VERSION 5.8 ;
BUSBITCHARS "[]" ;
DIVIDERCHAR "/" ;
CLEARANCEMEASURE EUCLIDEAN ;

SITE coresite
    SIZE 0.0450 BY 0.1680 ;
    CLASS CORE ;
    SYMMETRY Y ;
END coresite

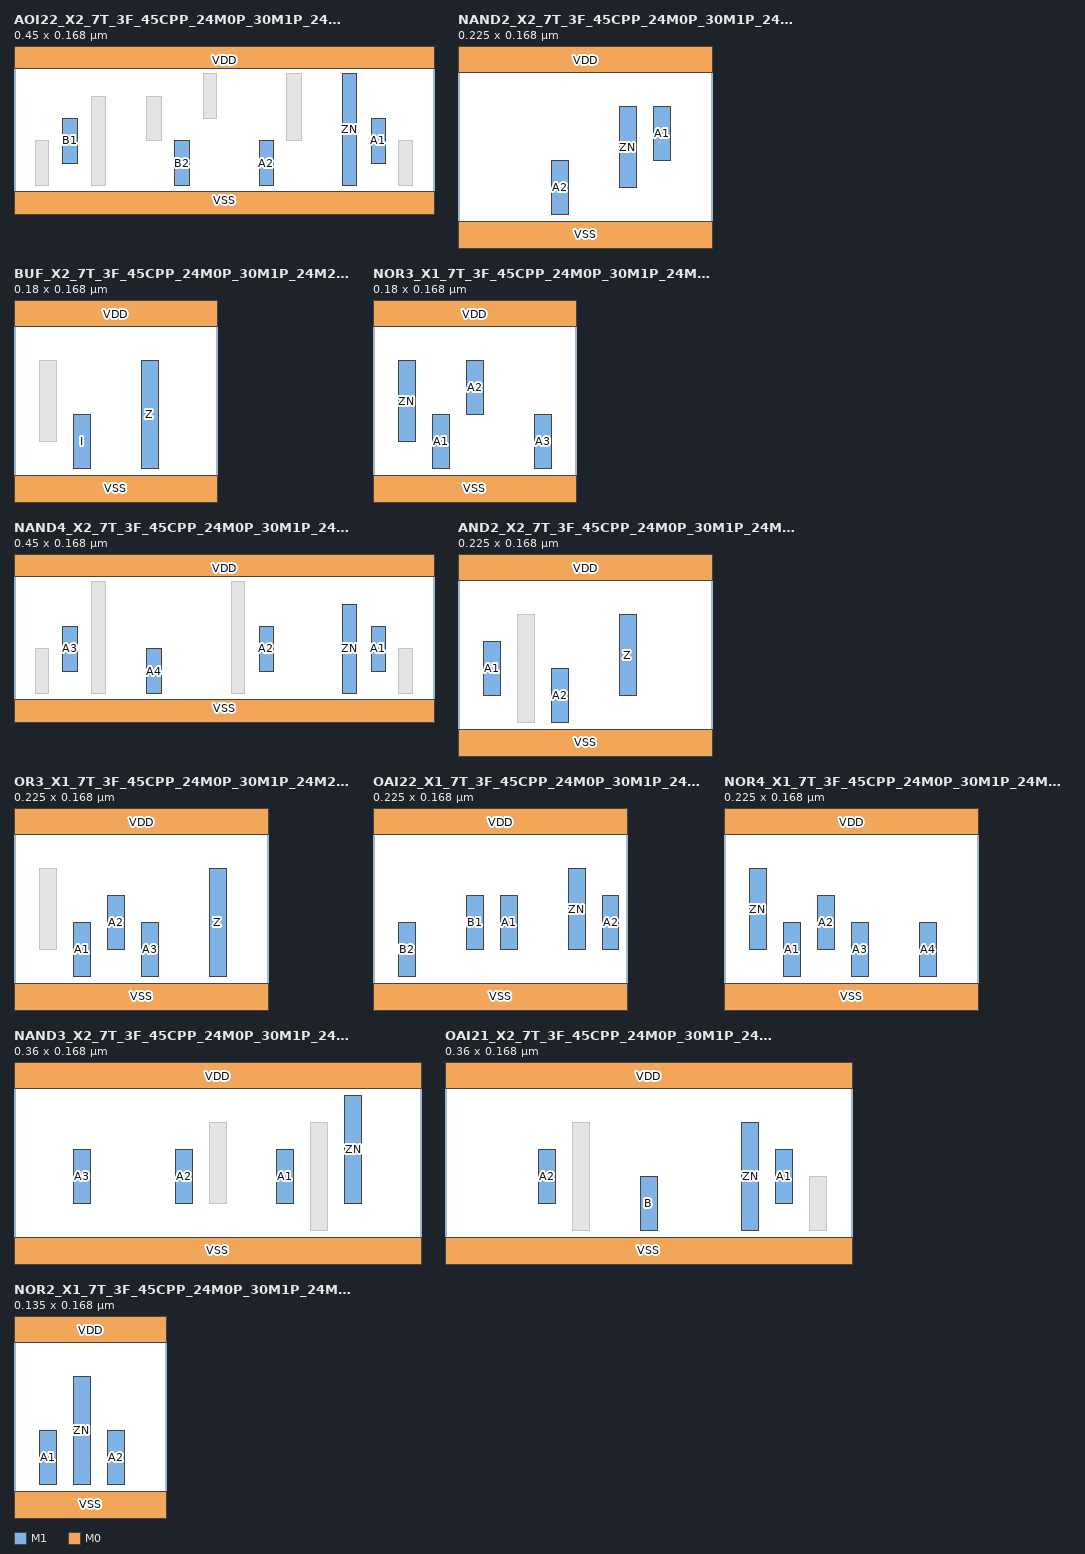
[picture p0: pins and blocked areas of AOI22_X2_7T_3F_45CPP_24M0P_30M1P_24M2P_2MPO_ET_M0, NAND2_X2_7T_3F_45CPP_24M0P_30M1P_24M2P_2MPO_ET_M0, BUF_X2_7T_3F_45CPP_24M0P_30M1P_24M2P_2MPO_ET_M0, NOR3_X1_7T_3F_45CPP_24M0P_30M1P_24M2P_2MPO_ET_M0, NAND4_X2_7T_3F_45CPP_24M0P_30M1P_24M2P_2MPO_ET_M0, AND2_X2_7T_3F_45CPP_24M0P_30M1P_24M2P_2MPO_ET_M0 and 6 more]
MACRO AOI22_X2_7T_3F_45CPP_24M0P_30M1P_24M2P_2MPO_ET_M0
  CLASS CORE ;
  ORIGIN 0 0 ;
  FOREIGN AOI22_X2_7T_3F_45CPP_24M0P_30M1P_24M2P_2MPO_ET_M0 0 0 ;
  SIZE 0.4500 BY 0.1680 ;
  SYMMETRY X Y ;
  SITE coresite ;
  PIN A1
    DIRECTION INPUT ;
    USE SIGNAL ;
    PORT
      LAYER M1 ;
        RECT 0.3825 0.0960 0.3975 0.0480 ;
    END
  END A1
  PIN A2
    DIRECTION INPUT ;
    USE SIGNAL ;
    PORT
      LAYER M1 ;
        RECT 0.2625 0.0720 0.2775 0.0240 ;
    END
  END A2
  PIN ZN
    DIRECTION OUTPUT ;
    USE SIGNAL ;
    PORT
      LAYER M1 ;
        RECT 0.3525 0.1440 0.3675 0.0240 ;
    END
  END ZN
  PIN B1
    DIRECTION INPUT ;
    USE SIGNAL ;
    PORT
      LAYER M1 ;
        RECT 0.0525 0.0960 0.0675 0.0480 ;
    END
  END B1
  PIN B2
    DIRECTION INPUT ;
    USE SIGNAL ;
    PORT
      LAYER M1 ;
        RECT 0.1725 0.0720 0.1875 0.0240 ;
    END
  END B2
  PIN VDD
    DIRECTION INOUT ;
    USE POWER ;
    SHAPE ABUTMENT ;
    PORT
      LAYER M0 ;
        RECT 0.0000 0.1500 0.4500 0.1860 ;
    END
  END VDD
  PIN VSS
    DIRECTION INOUT ;
    USE GROUND ;
    SHAPE ABUTMENT ;
    PORT
      LAYER M0 ;
        RECT 0.0000 -0.0180 0.4500 0.0180 ;
    END
  END VSS
  OBS
      LAYER M1 ;
        RECT 0.0225 0.0720 0.0375 0.0240 ;
        RECT 0.2025 0.1440 0.2175 0.0960 ;
        RECT 0.4125 0.0720 0.4275 0.0240 ;
        RECT 0.1425 0.1200 0.1575 0.0720 ;
        RECT 0.0825 0.1200 0.0975 0.0240 ;
        RECT 0.2925 0.1440 0.3075 0.0720 ;
  END
END AOI22_X2_7T_3F_45CPP_24M0P_30M1P_24M2P_2MPO_ET_M0

MACRO NAND2_X2_7T_3F_45CPP_24M0P_30M1P_24M2P_2MPO_ET_M0
  CLASS CORE ;
  ORIGIN 0 0 ;
  FOREIGN NAND2_X2_7T_3F_45CPP_24M0P_30M1P_24M2P_2MPO_ET_M0 0 0 ;
  SIZE 0.2250 BY 0.1680 ;
  SYMMETRY X Y ;
  SITE coresite ;
  PIN A2
    DIRECTION INPUT ;
    USE SIGNAL ;
    PORT
      LAYER M1 ;
        RECT 0.0825 0.0720 0.0975 0.0240 ;
    END
  END A2
  PIN A1
    DIRECTION INPUT ;
    USE SIGNAL ;
    PORT
      LAYER M1 ;
        RECT 0.1725 0.1200 0.1875 0.0720 ;
    END
  END A1
  PIN ZN
    DIRECTION OUTPUT ;
    USE SIGNAL ;
    PORT
      LAYER M1 ;
        RECT 0.1425 0.1200 0.1575 0.0480 ;
    END
  END ZN
  PIN VDD
    DIRECTION INOUT ;
    USE POWER ;
    SHAPE ABUTMENT ;
    PORT
      LAYER M0 ;
        RECT 0.0000 0.1500 0.2250 0.1860 ;
    END
  END VDD
  PIN VSS
    DIRECTION INOUT ;
    USE GROUND ;
    SHAPE ABUTMENT ;
    PORT
      LAYER M0 ;
        RECT 0.0000 -0.0180 0.2250 0.0180 ;
    END
  END VSS
END NAND2_X2_7T_3F_45CPP_24M0P_30M1P_24M2P_2MPO_ET_M0

MACRO BUF_X2_7T_3F_45CPP_24M0P_30M1P_24M2P_2MPO_ET_M0
  CLASS CORE ;
  ORIGIN 0 0 ;
  FOREIGN BUF_X2_7T_3F_45CPP_24M0P_30M1P_24M2P_2MPO_ET_M0 0 0 ;
  SIZE 0.1800 BY 0.1680 ;
  SYMMETRY X Y ;
  SITE coresite ;
  PIN Z
    DIRECTION OUTPUT ;
    USE SIGNAL ;
    PORT
      LAYER M1 ;
        RECT 0.1125 0.1200 0.1275 0.0240 ;
    END
  END Z
  PIN I
    DIRECTION INPUT ;
    USE SIGNAL ;
    PORT
      LAYER M1 ;
        RECT 0.0525 0.0720 0.0675 0.0240 ;
    END
  END I
  PIN VDD
    DIRECTION INOUT ;
    USE POWER ;
    SHAPE ABUTMENT ;
    PORT
      LAYER M0 ;
        RECT 0.0000 0.1500 0.1800 0.1860 ;
    END
  END VDD
  PIN VSS
    DIRECTION INOUT ;
    USE GROUND ;
    SHAPE ABUTMENT ;
    PORT
      LAYER M0 ;
        RECT 0.0000 -0.0180 0.1800 0.0180 ;
    END
  END VSS
  OBS
      LAYER M1 ;
        RECT 0.0225 0.1200 0.0375 0.0480 ;
  END
END BUF_X2_7T_3F_45CPP_24M0P_30M1P_24M2P_2MPO_ET_M0

MACRO NOR3_X1_7T_3F_45CPP_24M0P_30M1P_24M2P_2MPO_ET_M0
  CLASS CORE ;
  ORIGIN 0 0 ;
  FOREIGN NOR3_X1_7T_3F_45CPP_24M0P_30M1P_24M2P_2MPO_ET_M0 0 0 ;
  SIZE 0.1800 BY 0.1680 ;
  SYMMETRY X Y ;
  SITE coresite ;
  PIN A3
    DIRECTION INPUT ;
    USE SIGNAL ;
    PORT
      LAYER M1 ;
        RECT 0.1425 0.0720 0.1575 0.0240 ;
    END
  END A3
  PIN A2
    DIRECTION INPUT ;
    USE SIGNAL ;
    PORT
      LAYER M1 ;
        RECT 0.0825 0.1200 0.0975 0.0720 ;
    END
  END A2
  PIN A1
    DIRECTION INPUT ;
    USE SIGNAL ;
    PORT
      LAYER M1 ;
        RECT 0.0525 0.0720 0.0675 0.0240 ;
    END
  END A1
  PIN ZN
    DIRECTION OUTPUT ;
    USE SIGNAL ;
    PORT
      LAYER M1 ;
        RECT 0.0225 0.1200 0.0375 0.0480 ;
    END
  END ZN
  PIN VDD
    DIRECTION INOUT ;
    USE POWER ;
    SHAPE ABUTMENT ;
    PORT
      LAYER M0 ;
        RECT 0.0000 0.1500 0.1800 0.1860 ;
    END
  END VDD
  PIN VSS
    DIRECTION INOUT ;
    USE GROUND ;
    SHAPE ABUTMENT ;
    PORT
      LAYER M0 ;
        RECT 0.0000 -0.0180 0.1800 0.0180 ;
    END
  END VSS
END NOR3_X1_7T_3F_45CPP_24M0P_30M1P_24M2P_2MPO_ET_M0

MACRO NAND4_X2_7T_3F_45CPP_24M0P_30M1P_24M2P_2MPO_ET_M0
  CLASS CORE ;
  ORIGIN 0 0 ;
  FOREIGN NAND4_X2_7T_3F_45CPP_24M0P_30M1P_24M2P_2MPO_ET_M0 0 0 ;
  SIZE 0.4500 BY 0.1680 ;
  SYMMETRY X Y ;
  SITE coresite ;
  PIN ZN
    DIRECTION OUTPUT ;
    USE SIGNAL ;
    PORT
      LAYER M1 ;
        RECT 0.3525 0.1200 0.3675 0.0240 ;
    END
  END ZN
  PIN A1
    DIRECTION INPUT ;
    USE SIGNAL ;
    PORT
      LAYER M1 ;
        RECT 0.3825 0.0960 0.3975 0.0480 ;
    END
  END A1
  PIN A2
    DIRECTION INPUT ;
    USE SIGNAL ;
    PORT
      LAYER M1 ;
        RECT 0.2625 0.0960 0.2775 0.0480 ;
    END
  END A2
  PIN A3
    DIRECTION INPUT ;
    USE SIGNAL ;
    PORT
      LAYER M1 ;
        RECT 0.0525 0.0960 0.0675 0.0480 ;
    END
  END A3
  PIN A4
    DIRECTION INPUT ;
    USE SIGNAL ;
    PORT
      LAYER M1 ;
        RECT 0.1425 0.0720 0.1575 0.0240 ;
    END
  END A4
  PIN VDD
    DIRECTION INOUT ;
    USE POWER ;
    SHAPE ABUTMENT ;
    PORT
      LAYER M0 ;
        RECT 0.0000 0.1500 0.4500 0.1860 ;
    END
  END VDD
  PIN VSS
    DIRECTION INOUT ;
    USE GROUND ;
    SHAPE ABUTMENT ;
    PORT
      LAYER M0 ;
        RECT 0.0000 -0.0180 0.4500 0.0180 ;
    END
  END VSS
  OBS
      LAYER M1 ;
        RECT 0.0825 0.1440 0.0975 0.0240 ;
        RECT 0.2325 0.1440 0.2475 0.0240 ;
        RECT 0.0225 0.0720 0.0375 0.0240 ;
        RECT 0.4125 0.0720 0.4275 0.0240 ;
  END
END NAND4_X2_7T_3F_45CPP_24M0P_30M1P_24M2P_2MPO_ET_M0

MACRO AND2_X2_7T_3F_45CPP_24M0P_30M1P_24M2P_2MPO_ET_M0
  CLASS CORE ;
  ORIGIN 0 0 ;
  FOREIGN AND2_X2_7T_3F_45CPP_24M0P_30M1P_24M2P_2MPO_ET_M0 0 0 ;
  SIZE 0.2250 BY 0.1680 ;
  SYMMETRY X Y ;
  SITE coresite ;
  PIN Z
    DIRECTION OUTPUT ;
    USE SIGNAL ;
    PORT
      LAYER M1 ;
        RECT 0.1425 0.1200 0.1575 0.0480 ;
    END
  END Z
  PIN A1
    DIRECTION INPUT ;
    USE SIGNAL ;
    PORT
      LAYER M1 ;
        RECT 0.0225 0.0960 0.0375 0.0480 ;
    END
  END A1
  PIN A2
    DIRECTION INPUT ;
    USE SIGNAL ;
    PORT
      LAYER M1 ;
        RECT 0.0825 0.0720 0.0975 0.0240 ;
    END
  END A2
  PIN VDD
    DIRECTION INOUT ;
    USE POWER ;
    SHAPE ABUTMENT ;
    PORT
      LAYER M0 ;
        RECT 0.0000 0.1500 0.2250 0.1860 ;
    END
  END VDD
  PIN VSS
    DIRECTION INOUT ;
    USE GROUND ;
    SHAPE ABUTMENT ;
    PORT
      LAYER M0 ;
        RECT 0.0000 -0.0180 0.2250 0.0180 ;
    END
  END VSS
  OBS
      LAYER M1 ;
        RECT 0.0525 0.1200 0.0675 0.0240 ;
  END
END AND2_X2_7T_3F_45CPP_24M0P_30M1P_24M2P_2MPO_ET_M0

MACRO OR3_X1_7T_3F_45CPP_24M0P_30M1P_24M2P_2MPO_ET_M0
  CLASS CORE ;
  ORIGIN 0 0 ;
  FOREIGN OR3_X1_7T_3F_45CPP_24M0P_30M1P_24M2P_2MPO_ET_M0 0 0 ;
  SIZE 0.2250 BY 0.1680 ;
  SYMMETRY X Y ;
  SITE coresite ;
  PIN Z
    DIRECTION OUTPUT ;
    USE SIGNAL ;
    PORT
      LAYER M1 ;
        RECT 0.1725 0.1200 0.1875 0.0240 ;
    END
  END Z
  PIN A1
    DIRECTION INPUT ;
    USE SIGNAL ;
    PORT
      LAYER M1 ;
        RECT 0.0525 0.0720 0.0675 0.0240 ;
    END
  END A1
  PIN A2
    DIRECTION INPUT ;
    USE SIGNAL ;
    PORT
      LAYER M1 ;
        RECT 0.0825 0.0960 0.0975 0.0480 ;
    END
  END A2
  PIN A3
    DIRECTION INPUT ;
    USE SIGNAL ;
    PORT
      LAYER M1 ;
        RECT 0.1125 0.0720 0.1275 0.0240 ;
    END
  END A3
  PIN VDD
    DIRECTION INOUT ;
    USE POWER ;
    SHAPE ABUTMENT ;
    PORT
      LAYER M0 ;
        RECT 0.0000 0.1500 0.2250 0.1860 ;
    END
  END VDD
  PIN VSS
    DIRECTION INOUT ;
    USE GROUND ;
    SHAPE ABUTMENT ;
    PORT
      LAYER M0 ;
        RECT 0.0000 -0.0180 0.2250 0.0180 ;
    END
  END VSS
  OBS
      LAYER M1 ;
        RECT 0.0225 0.1200 0.0375 0.0480 ;
  END
END OR3_X1_7T_3F_45CPP_24M0P_30M1P_24M2P_2MPO_ET_M0

MACRO OAI22_X1_7T_3F_45CPP_24M0P_30M1P_24M2P_2MPO_ET_M0
  CLASS CORE ;
  ORIGIN 0 0 ;
  FOREIGN OAI22_X1_7T_3F_45CPP_24M0P_30M1P_24M2P_2MPO_ET_M0 0 0 ;
  SIZE 0.2250 BY 0.1680 ;
  SYMMETRY X Y ;
  SITE coresite ;
  PIN A2
    DIRECTION INPUT ;
    USE SIGNAL ;
    PORT
      LAYER M1 ;
        RECT 0.2025 0.0960 0.2175 0.0480 ;
    END
  END A2
  PIN ZN
    DIRECTION OUTPUT ;
    USE SIGNAL ;
    PORT
      LAYER M1 ;
        RECT 0.1725 0.1200 0.1875 0.0480 ;
    END
  END ZN
  PIN A1
    DIRECTION INPUT ;
    USE SIGNAL ;
    PORT
      LAYER M1 ;
        RECT 0.1125 0.0960 0.1275 0.0480 ;
    END
  END A1
  PIN B1
    DIRECTION INPUT ;
    USE SIGNAL ;
    PORT
      LAYER M1 ;
        RECT 0.0825 0.0960 0.0975 0.0480 ;
    END
  END B1
  PIN B2
    DIRECTION INPUT ;
    USE SIGNAL ;
    PORT
      LAYER M1 ;
        RECT 0.0225 0.0720 0.0375 0.0240 ;
    END
  END B2
  PIN VDD
    DIRECTION INOUT ;
    USE POWER ;
    SHAPE ABUTMENT ;
    PORT
      LAYER M0 ;
        RECT 0.0000 0.1500 0.2250 0.1860 ;
    END
  END VDD
  PIN VSS
    DIRECTION INOUT ;
    USE GROUND ;
    SHAPE ABUTMENT ;
    PORT
      LAYER M0 ;
        RECT 0.0000 -0.0180 0.2250 0.0180 ;
    END
  END VSS
END OAI22_X1_7T_3F_45CPP_24M0P_30M1P_24M2P_2MPO_ET_M0

MACRO NOR4_X1_7T_3F_45CPP_24M0P_30M1P_24M2P_2MPO_ET_M0
  CLASS CORE ;
  ORIGIN 0 0 ;
  FOREIGN NOR4_X1_7T_3F_45CPP_24M0P_30M1P_24M2P_2MPO_ET_M0 0 0 ;
  SIZE 0.2250 BY 0.1680 ;
  SYMMETRY X Y ;
  SITE coresite ;
  PIN A4
    DIRECTION INPUT ;
    USE SIGNAL ;
    PORT
      LAYER M1 ;
        RECT 0.1725 0.0720 0.1875 0.0240 ;
    END
  END A4
  PIN A3
    DIRECTION INPUT ;
    USE SIGNAL ;
    PORT
      LAYER M1 ;
        RECT 0.1125 0.0720 0.1275 0.0240 ;
    END
  END A3
  PIN A2
    DIRECTION INPUT ;
    USE SIGNAL ;
    PORT
      LAYER M1 ;
        RECT 0.0825 0.0960 0.0975 0.0480 ;
    END
  END A2
  PIN A1
    DIRECTION INPUT ;
    USE SIGNAL ;
    PORT
      LAYER M1 ;
        RECT 0.0525 0.0720 0.0675 0.0240 ;
    END
  END A1
  PIN ZN
    DIRECTION OUTPUT ;
    USE SIGNAL ;
    PORT
      LAYER M1 ;
        RECT 0.0225 0.1200 0.0375 0.0480 ;
    END
  END ZN
  PIN VDD
    DIRECTION INOUT ;
    USE POWER ;
    SHAPE ABUTMENT ;
    PORT
      LAYER M0 ;
        RECT 0.0000 0.1500 0.2250 0.1860 ;
    END
  END VDD
  PIN VSS
    DIRECTION INOUT ;
    USE GROUND ;
    SHAPE ABUTMENT ;
    PORT
      LAYER M0 ;
        RECT 0.0000 -0.0180 0.2250 0.0180 ;
    END
  END VSS
END NOR4_X1_7T_3F_45CPP_24M0P_30M1P_24M2P_2MPO_ET_M0

MACRO NAND3_X2_7T_3F_45CPP_24M0P_30M1P_24M2P_2MPO_ET_M0
  CLASS CORE ;
  ORIGIN 0 0 ;
  FOREIGN NAND3_X2_7T_3F_45CPP_24M0P_30M1P_24M2P_2MPO_ET_M0 0 0 ;
  SIZE 0.3600 BY 0.1680 ;
  SYMMETRY X Y ;
  SITE coresite ;
  PIN A1
    DIRECTION INPUT ;
    USE SIGNAL ;
    PORT
      LAYER M1 ;
        RECT 0.2325 0.0960 0.2475 0.0480 ;
    END
  END A1
  PIN ZN
    DIRECTION OUTPUT ;
    USE SIGNAL ;
    PORT
      LAYER M1 ;
        RECT 0.2925 0.1440 0.3075 0.0480 ;
    END
  END ZN
  PIN A2
    DIRECTION INPUT ;
    USE SIGNAL ;
    PORT
      LAYER M1 ;
        RECT 0.1425 0.0960 0.1575 0.0480 ;
    END
  END A2
  PIN A3
    DIRECTION INPUT ;
    USE SIGNAL ;
    PORT
      LAYER M1 ;
        RECT 0.0525 0.0960 0.0675 0.0480 ;
    END
  END A3
  PIN VDD
    DIRECTION INOUT ;
    USE POWER ;
    SHAPE ABUTMENT ;
    PORT
      LAYER M0 ;
        RECT 0.0000 0.1500 0.3600 0.1860 ;
    END
  END VDD
  PIN VSS
    DIRECTION INOUT ;
    USE GROUND ;
    SHAPE ABUTMENT ;
    PORT
      LAYER M0 ;
        RECT 0.0000 -0.0180 0.3600 0.0180 ;
    END
  END VSS
  OBS
      LAYER M1 ;
        RECT 0.2625 0.1200 0.2775 0.0240 ;
        RECT 0.1725 0.1200 0.1875 0.0480 ;
  END
END NAND3_X2_7T_3F_45CPP_24M0P_30M1P_24M2P_2MPO_ET_M0

MACRO OAI21_X2_7T_3F_45CPP_24M0P_30M1P_24M2P_2MPO_ET_M0
  CLASS CORE ;
  ORIGIN 0 0 ;
  FOREIGN OAI21_X2_7T_3F_45CPP_24M0P_30M1P_24M2P_2MPO_ET_M0 0 0 ;
  SIZE 0.3600 BY 0.1680 ;
  SYMMETRY X Y ;
  SITE coresite ;
  PIN A2
    DIRECTION INPUT ;
    USE SIGNAL ;
    PORT
      LAYER M1 ;
        RECT 0.0825 0.0960 0.0975 0.0480 ;
    END
  END A2
  PIN A1
    DIRECTION INPUT ;
    USE SIGNAL ;
    PORT
      LAYER M1 ;
        RECT 0.2925 0.0960 0.3075 0.0480 ;
    END
  END A1
  PIN ZN
    DIRECTION OUTPUT ;
    USE SIGNAL ;
    PORT
      LAYER M1 ;
        RECT 0.2625 0.1200 0.2775 0.0240 ;
    END
  END ZN
  PIN B
    DIRECTION INPUT ;
    USE SIGNAL ;
    PORT
      LAYER M1 ;
        RECT 0.1725 0.0720 0.1875 0.0240 ;
    END
  END B
  PIN VDD
    DIRECTION INOUT ;
    USE POWER ;
    SHAPE ABUTMENT ;
    PORT
      LAYER M0 ;
        RECT 0.0000 0.1500 0.3600 0.1860 ;
    END
  END VDD
  PIN VSS
    DIRECTION INOUT ;
    USE GROUND ;
    SHAPE ABUTMENT ;
    PORT
      LAYER M0 ;
        RECT 0.0000 -0.0180 0.3600 0.0180 ;
    END
  END VSS
  OBS
      LAYER M1 ;
        RECT 0.3225 0.0720 0.3375 0.0240 ;
        RECT 0.1125 0.1200 0.1275 0.0240 ;
  END
END OAI21_X2_7T_3F_45CPP_24M0P_30M1P_24M2P_2MPO_ET_M0

MACRO NOR2_X1_7T_3F_45CPP_24M0P_30M1P_24M2P_2MPO_ET_M0
  CLASS CORE ;
  ORIGIN 0 0 ;
  FOREIGN NOR2_X1_7T_3F_45CPP_24M0P_30M1P_24M2P_2MPO_ET_M0 0 0 ;
  SIZE 0.1350 BY 0.1680 ;
  SYMMETRY X Y ;
  SITE coresite ;
  PIN A2
    DIRECTION INPUT ;
    USE SIGNAL ;
    PORT
      LAYER M1 ;
        RECT 0.0825 0.0720 0.0975 0.0240 ;
    END
  END A2
  PIN A1
    DIRECTION INPUT ;
    USE SIGNAL ;
    PORT
      LAYER M1 ;
        RECT 0.0225 0.0720 0.0375 0.0240 ;
    END
  END A1
  PIN ZN
    DIRECTION OUTPUT ;
    USE SIGNAL ;
    PORT
      LAYER M1 ;
        RECT 0.0525 0.1200 0.0675 0.0240 ;
    END
  END ZN
  PIN VDD
    DIRECTION INOUT ;
    USE POWER ;
    SHAPE ABUTMENT ;
    PORT
      LAYER M0 ;
        RECT 0.0000 0.1500 0.1350 0.1860 ;
    END
  END VDD
  PIN VSS
    DIRECTION INOUT ;
    USE GROUND ;
    SHAPE ABUTMENT ;
    PORT
      LAYER M0 ;
        RECT 0.0000 -0.0180 0.1350 0.0180 ;
    END
  END VSS
END NOR2_X1_7T_3F_45CPP_24M0P_30M1P_24M2P_2MPO_ET_M0

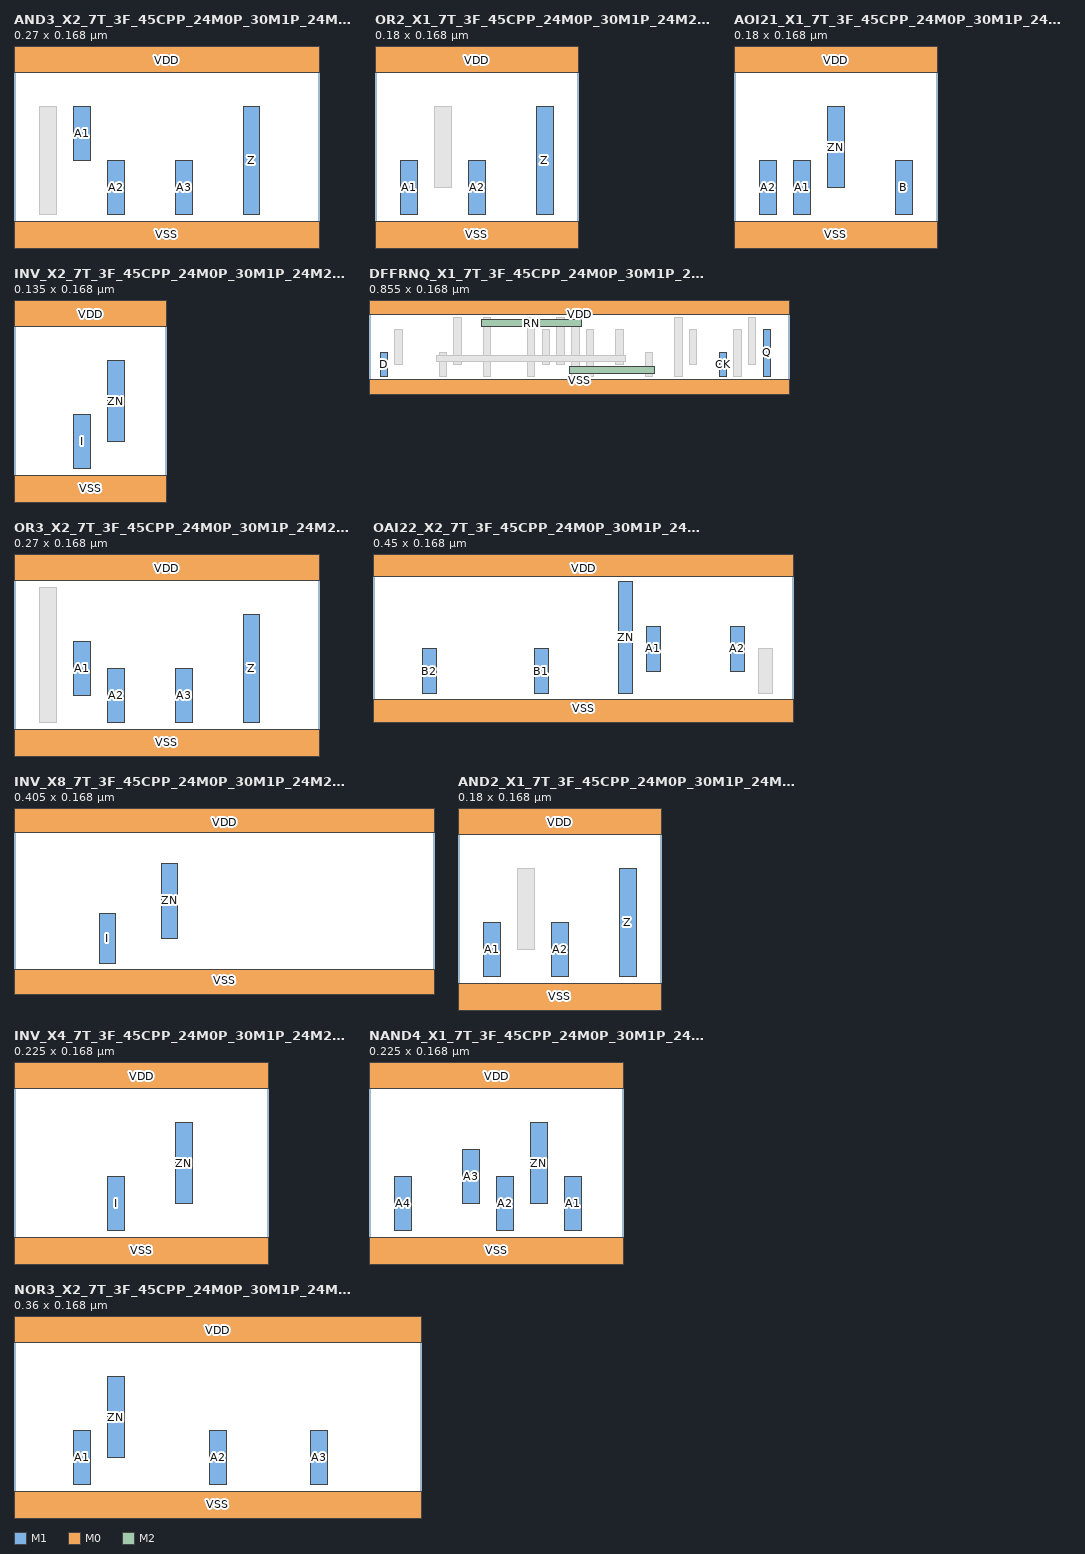
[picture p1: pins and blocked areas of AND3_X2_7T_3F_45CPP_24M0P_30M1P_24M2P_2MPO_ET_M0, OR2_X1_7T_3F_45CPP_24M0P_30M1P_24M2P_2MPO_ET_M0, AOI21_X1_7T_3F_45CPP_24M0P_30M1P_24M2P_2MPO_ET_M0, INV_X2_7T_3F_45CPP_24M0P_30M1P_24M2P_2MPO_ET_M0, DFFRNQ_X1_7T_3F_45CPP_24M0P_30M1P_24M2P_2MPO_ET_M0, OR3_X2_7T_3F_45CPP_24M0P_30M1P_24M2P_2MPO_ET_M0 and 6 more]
MACRO AND3_X2_7T_3F_45CPP_24M0P_30M1P_24M2P_2MPO_ET_M0
  CLASS CORE ;
  ORIGIN 0 0 ;
  FOREIGN AND3_X2_7T_3F_45CPP_24M0P_30M1P_24M2P_2MPO_ET_M0 0 0 ;
  SIZE 0.2700 BY 0.1680 ;
  SYMMETRY X Y ;
  SITE coresite ;
  PIN Z
    DIRECTION OUTPUT ;
    USE SIGNAL ;
    PORT
      LAYER M1 ;
        RECT 0.2025 0.1200 0.2175 0.0240 ;
    END
  END Z
  PIN A3
    DIRECTION INPUT ;
    USE SIGNAL ;
    PORT
      LAYER M1 ;
        RECT 0.1425 0.0720 0.1575 0.0240 ;
    END
  END A3
  PIN A1
    DIRECTION INPUT ;
    USE SIGNAL ;
    PORT
      LAYER M1 ;
        RECT 0.0525 0.1200 0.0675 0.0720 ;
    END
  END A1
  PIN A2
    DIRECTION INPUT ;
    USE SIGNAL ;
    PORT
      LAYER M1 ;
        RECT 0.0825 0.0720 0.0975 0.0240 ;
    END
  END A2
  PIN VDD
    DIRECTION INOUT ;
    USE POWER ;
    SHAPE ABUTMENT ;
    PORT
      LAYER M0 ;
        RECT 0.0000 0.1500 0.2700 0.1860 ;
    END
  END VDD
  PIN VSS
    DIRECTION INOUT ;
    USE GROUND ;
    SHAPE ABUTMENT ;
    PORT
      LAYER M0 ;
        RECT 0.0000 -0.0180 0.2700 0.0180 ;
    END
  END VSS
  OBS
      LAYER M1 ;
        RECT 0.0225 0.1200 0.0375 0.0240 ;
  END
END AND3_X2_7T_3F_45CPP_24M0P_30M1P_24M2P_2MPO_ET_M0

MACRO OR2_X1_7T_3F_45CPP_24M0P_30M1P_24M2P_2MPO_ET_M0
  CLASS CORE ;
  ORIGIN 0 0 ;
  FOREIGN OR2_X1_7T_3F_45CPP_24M0P_30M1P_24M2P_2MPO_ET_M0 0 0 ;
  SIZE 0.1800 BY 0.1680 ;
  SYMMETRY X Y ;
  SITE coresite ;
  PIN Z
    DIRECTION OUTPUT ;
    USE SIGNAL ;
    PORT
      LAYER M1 ;
        RECT 0.1425 0.1200 0.1575 0.0240 ;
    END
  END Z
  PIN A1
    DIRECTION INPUT ;
    USE SIGNAL ;
    PORT
      LAYER M1 ;
        RECT 0.0225 0.0720 0.0375 0.0240 ;
    END
  END A1
  PIN A2
    DIRECTION INPUT ;
    USE SIGNAL ;
    PORT
      LAYER M1 ;
        RECT 0.0825 0.0720 0.0975 0.0240 ;
    END
  END A2
  PIN VDD
    DIRECTION INOUT ;
    USE POWER ;
    SHAPE ABUTMENT ;
    PORT
      LAYER M0 ;
        RECT 0.0000 0.1500 0.1800 0.1860 ;
    END
  END VDD
  PIN VSS
    DIRECTION INOUT ;
    USE GROUND ;
    SHAPE ABUTMENT ;
    PORT
      LAYER M0 ;
        RECT 0.0000 -0.0180 0.1800 0.0180 ;
    END
  END VSS
  OBS
      LAYER M1 ;
        RECT 0.0525 0.1200 0.0675 0.0480 ;
  END
END OR2_X1_7T_3F_45CPP_24M0P_30M1P_24M2P_2MPO_ET_M0

MACRO AOI21_X1_7T_3F_45CPP_24M0P_30M1P_24M2P_2MPO_ET_M0
  CLASS CORE ;
  ORIGIN 0 0 ;
  FOREIGN AOI21_X1_7T_3F_45CPP_24M0P_30M1P_24M2P_2MPO_ET_M0 0 0 ;
  SIZE 0.1800 BY 0.1680 ;
  SYMMETRY X Y ;
  SITE coresite ;
  PIN B
    DIRECTION INPUT ;
    USE SIGNAL ;
    PORT
      LAYER M1 ;
        RECT 0.1425 0.0720 0.1575 0.0240 ;
    END
  END B
  PIN ZN
    DIRECTION OUTPUT ;
    USE SIGNAL ;
    PORT
      LAYER M1 ;
        RECT 0.0825 0.1200 0.0975 0.0480 ;
    END
  END ZN
  PIN A1
    DIRECTION INPUT ;
    USE SIGNAL ;
    PORT
      LAYER M1 ;
        RECT 0.0525 0.0720 0.0675 0.0240 ;
    END
  END A1
  PIN A2
    DIRECTION INPUT ;
    USE SIGNAL ;
    PORT
      LAYER M1 ;
        RECT 0.0225 0.0720 0.0375 0.0240 ;
    END
  END A2
  PIN VDD
    DIRECTION INOUT ;
    USE POWER ;
    SHAPE ABUTMENT ;
    PORT
      LAYER M0 ;
        RECT 0.0000 0.1500 0.1800 0.1860 ;
    END
  END VDD
  PIN VSS
    DIRECTION INOUT ;
    USE GROUND ;
    SHAPE ABUTMENT ;
    PORT
      LAYER M0 ;
        RECT 0.0000 -0.0180 0.1800 0.0180 ;
    END
  END VSS
END AOI21_X1_7T_3F_45CPP_24M0P_30M1P_24M2P_2MPO_ET_M0

MACRO INV_X2_7T_3F_45CPP_24M0P_30M1P_24M2P_2MPO_ET_M0
  CLASS CORE ;
  ORIGIN 0 0 ;
  FOREIGN INV_X2_7T_3F_45CPP_24M0P_30M1P_24M2P_2MPO_ET_M0 0 0 ;
  SIZE 0.1350 BY 0.1680 ;
  SYMMETRY X Y ;
  SITE coresite ;
  PIN ZN
    DIRECTION OUTPUT ;
    USE SIGNAL ;
    PORT
      LAYER M1 ;
        RECT 0.0825 0.1200 0.0975 0.0480 ;
    END
  END ZN
  PIN I
    DIRECTION INPUT ;
    USE SIGNAL ;
    PORT
      LAYER M1 ;
        RECT 0.0525 0.0720 0.0675 0.0240 ;
    END
  END I
  PIN VDD
    DIRECTION INOUT ;
    USE POWER ;
    SHAPE ABUTMENT ;
    PORT
      LAYER M0 ;
        RECT 0.0000 0.1500 0.1350 0.1860 ;
    END
  END VDD
  PIN VSS
    DIRECTION INOUT ;
    USE GROUND ;
    SHAPE ABUTMENT ;
    PORT
      LAYER M0 ;
        RECT 0.0000 -0.0180 0.1350 0.0180 ;
    END
  END VSS
END INV_X2_7T_3F_45CPP_24M0P_30M1P_24M2P_2MPO_ET_M0

MACRO DFFRNQ_X1_7T_3F_45CPP_24M0P_30M1P_24M2P_2MPO_ET_M0
  CLASS CORE ;
  ORIGIN 0 0 ;
  FOREIGN DFFRNQ_X1_7T_3F_45CPP_24M0P_30M1P_24M2P_2MPO_ET_M0 0 0 ;
  SIZE 0.8550 BY 0.1680 ;
  SYMMETRY X Y ;
  SITE coresite ;
  PIN Q
    DIRECTION OUTPUT ;
    USE SIGNAL ;
    PORT
      LAYER M1 ;
        RECT 0.8025 0.1200 0.8175 0.0240 ;
    END
  END Q
  PIN RN
    DIRECTION INPUT ;
    USE SIGNAL ;
    PORT
      LAYER M2 ;
        RECT 0.4080 0.0290 0.5820 0.0430 ;
        RECT 0.2280 0.1250 0.4320 0.1390 ;
    END
  END RN
  PIN D
    DIRECTION INPUT ;
    USE SIGNAL ;
    PORT
      LAYER M1 ;
        RECT 0.0225 0.0720 0.0375 0.0240 ;
    END
  END D
  PIN CK
    DIRECTION INPUT ;
    USE SIGNAL ;
    PORT
      LAYER M1 ;
        RECT 0.7125 0.0720 0.7275 0.0240 ;
    END
  END CK
  PIN VDD
    DIRECTION INOUT ;
    USE POWER ;
    SHAPE ABUTMENT ;
    PORT
      LAYER M0 ;
        RECT 0.0000 0.1500 0.8550 0.1860 ;
    END
  END VDD
  PIN VSS
    DIRECTION INOUT ;
    USE GROUND ;
    SHAPE ABUTMENT ;
    PORT
      LAYER M0 ;
        RECT 0.0000 -0.0180 0.8550 0.0180 ;
    END
  END VSS
  OBS
      LAYER V1 ;
        RECT 0.5030 0.0530 0.5170 0.0670 ;
        RECT 0.3830 0.0530 0.3970 0.0670 ;
        RECT 0.1430 0.0530 0.1570 0.0670 ;
        RECT 0.5630 0.0290 0.5770 0.0430 ;
        RECT 0.4130 0.0290 0.4270 0.0430 ;
        RECT 0.4130 0.1250 0.4270 0.1390 ;
        RECT 0.2330 0.1250 0.2470 0.1390 ;
      LAYER M1 ;
        RECT 0.4425 0.1200 0.4575 0.0240 ;
        RECT 0.6225 0.1440 0.6375 0.0240 ;
        RECT 0.1725 0.1440 0.1875 0.0480 ;
        RECT 0.3825 0.1440 0.3975 0.0480 ;
        RECT 0.7425 0.1200 0.7575 0.0240 ;
        RECT 0.5025 0.1200 0.5175 0.0480 ;
        RECT 0.3525 0.1200 0.3675 0.0480 ;
        RECT 0.6525 0.1200 0.6675 0.0480 ;
        RECT 0.0525 0.1200 0.0675 0.0480 ;
        RECT 0.3225 0.1440 0.3375 0.0240 ;
        RECT 0.7725 0.1440 0.7875 0.0480 ;
        RECT 0.1425 0.0720 0.1575 0.0240 ;
        RECT 0.4125 0.1440 0.4275 0.0240 ;
        RECT 0.2325 0.1440 0.2475 0.0240 ;
        RECT 0.5625 0.0720 0.5775 0.0240 ;
      LAYER M2 ;
        RECT 0.1380 0.0530 0.5220 0.0670 ;
  END
END DFFRNQ_X1_7T_3F_45CPP_24M0P_30M1P_24M2P_2MPO_ET_M0

MACRO OR3_X2_7T_3F_45CPP_24M0P_30M1P_24M2P_2MPO_ET_M0
  CLASS CORE ;
  ORIGIN 0 0 ;
  FOREIGN OR3_X2_7T_3F_45CPP_24M0P_30M1P_24M2P_2MPO_ET_M0 0 0 ;
  SIZE 0.2700 BY 0.1680 ;
  SYMMETRY X Y ;
  SITE coresite ;
  PIN Z
    DIRECTION OUTPUT ;
    USE SIGNAL ;
    PORT
      LAYER M1 ;
        RECT 0.2025 0.1200 0.2175 0.0240 ;
    END
  END Z
  PIN A3
    DIRECTION INPUT ;
    USE SIGNAL ;
    PORT
      LAYER M1 ;
        RECT 0.1425 0.0720 0.1575 0.0240 ;
    END
  END A3
  PIN A1
    DIRECTION INPUT ;
    USE SIGNAL ;
    PORT
      LAYER M1 ;
        RECT 0.0525 0.0960 0.0675 0.0480 ;
    END
  END A1
  PIN A2
    DIRECTION INPUT ;
    USE SIGNAL ;
    PORT
      LAYER M1 ;
        RECT 0.0825 0.0720 0.0975 0.0240 ;
    END
  END A2
  PIN VDD
    DIRECTION INOUT ;
    USE POWER ;
    SHAPE ABUTMENT ;
    PORT
      LAYER M0 ;
        RECT 0.0000 0.1500 0.2700 0.1860 ;
    END
  END VDD
  PIN VSS
    DIRECTION INOUT ;
    USE GROUND ;
    SHAPE ABUTMENT ;
    PORT
      LAYER M0 ;
        RECT 0.0000 -0.0180 0.2700 0.0180 ;
    END
  END VSS
  OBS
      LAYER M1 ;
        RECT 0.0225 0.1440 0.0375 0.0240 ;
  END
END OR3_X2_7T_3F_45CPP_24M0P_30M1P_24M2P_2MPO_ET_M0

MACRO OAI22_X2_7T_3F_45CPP_24M0P_30M1P_24M2P_2MPO_ET_M0
  CLASS CORE ;
  ORIGIN 0 0 ;
  FOREIGN OAI22_X2_7T_3F_45CPP_24M0P_30M1P_24M2P_2MPO_ET_M0 0 0 ;
  SIZE 0.4500 BY 0.1680 ;
  SYMMETRY X Y ;
  SITE coresite ;
  PIN A1
    DIRECTION INPUT ;
    USE SIGNAL ;
    PORT
      LAYER M1 ;
        RECT 0.2925 0.0960 0.3075 0.0480 ;
    END
  END A1
  PIN ZN
    DIRECTION OUTPUT ;
    USE SIGNAL ;
    PORT
      LAYER M1 ;
        RECT 0.2625 0.1440 0.2775 0.0240 ;
    END
  END ZN
  PIN A2
    DIRECTION INPUT ;
    USE SIGNAL ;
    PORT
      LAYER M1 ;
        RECT 0.3825 0.0960 0.3975 0.0480 ;
    END
  END A2
  PIN B1
    DIRECTION INPUT ;
    USE SIGNAL ;
    PORT
      LAYER M1 ;
        RECT 0.1725 0.0720 0.1875 0.0240 ;
    END
  END B1
  PIN B2
    DIRECTION INPUT ;
    USE SIGNAL ;
    PORT
      LAYER M1 ;
        RECT 0.0525 0.0720 0.0675 0.0240 ;
    END
  END B2
  PIN VDD
    DIRECTION INOUT ;
    USE POWER ;
    SHAPE ABUTMENT ;
    PORT
      LAYER M0 ;
        RECT 0.0000 0.1500 0.4500 0.1860 ;
    END
  END VDD
  PIN VSS
    DIRECTION INOUT ;
    USE GROUND ;
    SHAPE ABUTMENT ;
    PORT
      LAYER M0 ;
        RECT 0.0000 -0.0180 0.4500 0.0180 ;
    END
  END VSS
  OBS
      LAYER M1 ;
        RECT 0.4125 0.0720 0.4275 0.0240 ;
  END
END OAI22_X2_7T_3F_45CPP_24M0P_30M1P_24M2P_2MPO_ET_M0

MACRO INV_X8_7T_3F_45CPP_24M0P_30M1P_24M2P_2MPO_ET_M0
  CLASS CORE ;
  ORIGIN 0 0 ;
  FOREIGN INV_X8_7T_3F_45CPP_24M0P_30M1P_24M2P_2MPO_ET_M0 0 0 ;
  SIZE 0.4050 BY 0.1680 ;
  SYMMETRY X Y ;
  SITE coresite ;
  PIN ZN
    DIRECTION OUTPUT ;
    USE SIGNAL ;
    PORT
      LAYER M1 ;
        RECT 0.1425 0.1200 0.1575 0.0480 ;
    END
  END ZN
  PIN I
    DIRECTION INPUT ;
    USE SIGNAL ;
    PORT
      LAYER M1 ;
        RECT 0.0825 0.0720 0.0975 0.0240 ;
    END
  END I
  PIN VDD
    DIRECTION INOUT ;
    USE POWER ;
    SHAPE ABUTMENT ;
    PORT
      LAYER M0 ;
        RECT 0.0000 0.1500 0.4050 0.1860 ;
    END
  END VDD
  PIN VSS
    DIRECTION INOUT ;
    USE GROUND ;
    SHAPE ABUTMENT ;
    PORT
      LAYER M0 ;
        RECT 0.0000 -0.0180 0.4050 0.0180 ;
    END
  END VSS
END INV_X8_7T_3F_45CPP_24M0P_30M1P_24M2P_2MPO_ET_M0

MACRO AND2_X1_7T_3F_45CPP_24M0P_30M1P_24M2P_2MPO_ET_M0
  CLASS CORE ;
  ORIGIN 0 0 ;
  FOREIGN AND2_X1_7T_3F_45CPP_24M0P_30M1P_24M2P_2MPO_ET_M0 0 0 ;
  SIZE 0.1800 BY 0.1680 ;
  SYMMETRY X Y ;
  SITE coresite ;
  PIN Z
    DIRECTION OUTPUT ;
    USE SIGNAL ;
    PORT
      LAYER M1 ;
        RECT 0.1425 0.1200 0.1575 0.0240 ;
    END
  END Z
  PIN A1
    DIRECTION INPUT ;
    USE SIGNAL ;
    PORT
      LAYER M1 ;
        RECT 0.0225 0.0720 0.0375 0.0240 ;
    END
  END A1
  PIN A2
    DIRECTION INPUT ;
    USE SIGNAL ;
    PORT
      LAYER M1 ;
        RECT 0.0825 0.0720 0.0975 0.0240 ;
    END
  END A2
  PIN VDD
    DIRECTION INOUT ;
    USE POWER ;
    SHAPE ABUTMENT ;
    PORT
      LAYER M0 ;
        RECT 0.0000 0.1500 0.1800 0.1860 ;
    END
  END VDD
  PIN VSS
    DIRECTION INOUT ;
    USE GROUND ;
    SHAPE ABUTMENT ;
    PORT
      LAYER M0 ;
        RECT 0.0000 -0.0180 0.1800 0.0180 ;
    END
  END VSS
  OBS
      LAYER M1 ;
        RECT 0.0525 0.1200 0.0675 0.0480 ;
  END
END AND2_X1_7T_3F_45CPP_24M0P_30M1P_24M2P_2MPO_ET_M0

MACRO INV_X4_7T_3F_45CPP_24M0P_30M1P_24M2P_2MPO_ET_M0
  CLASS CORE ;
  ORIGIN 0 0 ;
  FOREIGN INV_X4_7T_3F_45CPP_24M0P_30M1P_24M2P_2MPO_ET_M0 0 0 ;
  SIZE 0.2250 BY 0.1680 ;
  SYMMETRY X Y ;
  SITE coresite ;
  PIN ZN
    DIRECTION OUTPUT ;
    USE SIGNAL ;
    PORT
      LAYER M1 ;
        RECT 0.1425 0.1200 0.1575 0.0480 ;
    END
  END ZN
  PIN I
    DIRECTION INPUT ;
    USE SIGNAL ;
    PORT
      LAYER M1 ;
        RECT 0.0825 0.0720 0.0975 0.0240 ;
    END
  END I
  PIN VDD
    DIRECTION INOUT ;
    USE POWER ;
    SHAPE ABUTMENT ;
    PORT
      LAYER M0 ;
        RECT 0.0000 0.1500 0.2250 0.1860 ;
    END
  END VDD
  PIN VSS
    DIRECTION INOUT ;
    USE GROUND ;
    SHAPE ABUTMENT ;
    PORT
      LAYER M0 ;
        RECT 0.0000 -0.0180 0.2250 0.0180 ;
    END
  END VSS
END INV_X4_7T_3F_45CPP_24M0P_30M1P_24M2P_2MPO_ET_M0

MACRO NAND4_X1_7T_3F_45CPP_24M0P_30M1P_24M2P_2MPO_ET_M0
  CLASS CORE ;
  ORIGIN 0 0 ;
  FOREIGN NAND4_X1_7T_3F_45CPP_24M0P_30M1P_24M2P_2MPO_ET_M0 0 0 ;
  SIZE 0.2250 BY 0.1680 ;
  SYMMETRY X Y ;
  SITE coresite ;
  PIN ZN
    DIRECTION OUTPUT ;
    USE SIGNAL ;
    PORT
      LAYER M1 ;
        RECT 0.1425 0.1200 0.1575 0.0480 ;
    END
  END ZN
  PIN A1
    DIRECTION INPUT ;
    USE SIGNAL ;
    PORT
      LAYER M1 ;
        RECT 0.1725 0.0720 0.1875 0.0240 ;
    END
  END A1
  PIN A2
    DIRECTION INPUT ;
    USE SIGNAL ;
    PORT
      LAYER M1 ;
        RECT 0.1125 0.0720 0.1275 0.0240 ;
    END
  END A2
  PIN A3
    DIRECTION INPUT ;
    USE SIGNAL ;
    PORT
      LAYER M1 ;
        RECT 0.0825 0.0960 0.0975 0.0480 ;
    END
  END A3
  PIN A4
    DIRECTION INPUT ;
    USE SIGNAL ;
    PORT
      LAYER M1 ;
        RECT 0.0225 0.0720 0.0375 0.0240 ;
    END
  END A4
  PIN VDD
    DIRECTION INOUT ;
    USE POWER ;
    SHAPE ABUTMENT ;
    PORT
      LAYER M0 ;
        RECT 0.0000 0.1500 0.2250 0.1860 ;
    END
  END VDD
  PIN VSS
    DIRECTION INOUT ;
    USE GROUND ;
    SHAPE ABUTMENT ;
    PORT
      LAYER M0 ;
        RECT 0.0000 -0.0180 0.2250 0.0180 ;
    END
  END VSS
END NAND4_X1_7T_3F_45CPP_24M0P_30M1P_24M2P_2MPO_ET_M0

MACRO NOR3_X2_7T_3F_45CPP_24M0P_30M1P_24M2P_2MPO_ET_M0
  CLASS CORE ;
  ORIGIN 0 0 ;
  FOREIGN NOR3_X2_7T_3F_45CPP_24M0P_30M1P_24M2P_2MPO_ET_M0 0 0 ;
  SIZE 0.3600 BY 0.1680 ;
  SYMMETRY X Y ;
  SITE coresite ;
  PIN A3
    DIRECTION INPUT ;
    USE SIGNAL ;
    PORT
      LAYER M1 ;
        RECT 0.2625 0.0720 0.2775 0.0240 ;
    END
  END A3
  PIN A2
    DIRECTION INPUT ;
    USE SIGNAL ;
    PORT
      LAYER M1 ;
        RECT 0.1725 0.0720 0.1875 0.0240 ;
    END
  END A2
  PIN A1
    DIRECTION INPUT ;
    USE SIGNAL ;
    PORT
      LAYER M1 ;
        RECT 0.0525 0.0720 0.0675 0.0240 ;
    END
  END A1
  PIN ZN
    DIRECTION OUTPUT ;
    USE SIGNAL ;
    PORT
      LAYER M1 ;
        RECT 0.0825 0.1200 0.0975 0.0480 ;
    END
  END ZN
  PIN VDD
    DIRECTION INOUT ;
    USE POWER ;
    SHAPE ABUTMENT ;
    PORT
      LAYER M0 ;
        RECT 0.0000 0.1500 0.3600 0.1860 ;
    END
  END VDD
  PIN VSS
    DIRECTION INOUT ;
    USE GROUND ;
    SHAPE ABUTMENT ;
    PORT
      LAYER M0 ;
        RECT 0.0000 -0.0180 0.3600 0.0180 ;
    END
  END VSS
END NOR3_X2_7T_3F_45CPP_24M0P_30M1P_24M2P_2MPO_ET_M0

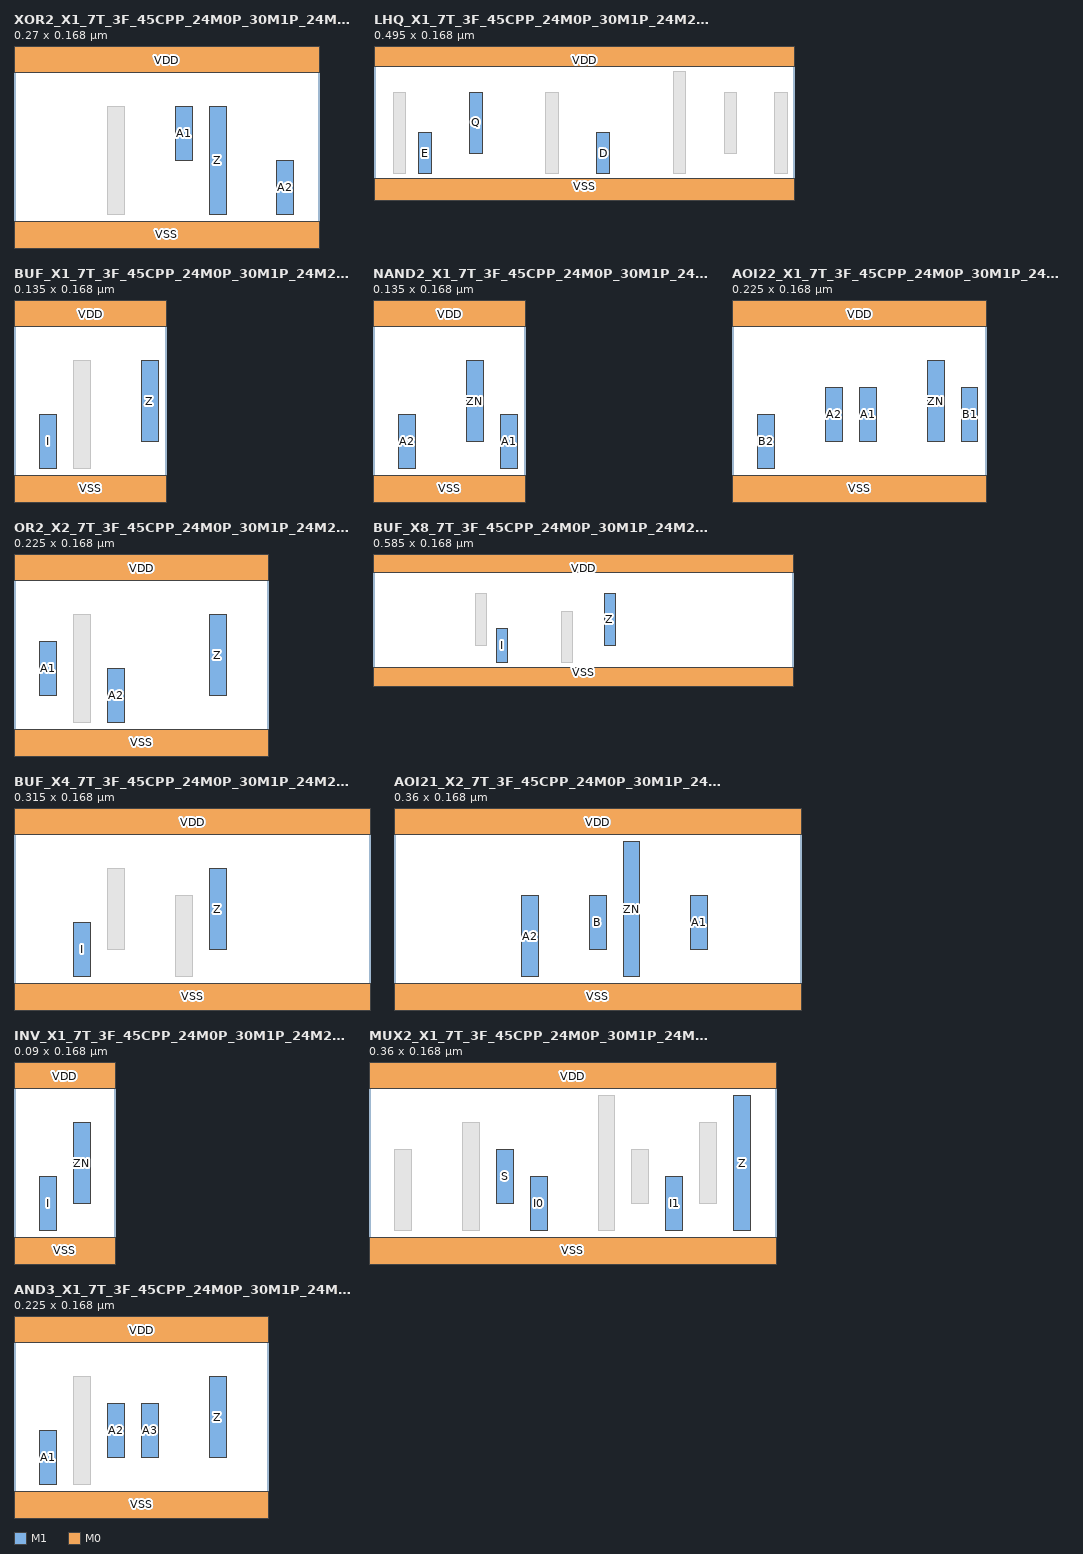
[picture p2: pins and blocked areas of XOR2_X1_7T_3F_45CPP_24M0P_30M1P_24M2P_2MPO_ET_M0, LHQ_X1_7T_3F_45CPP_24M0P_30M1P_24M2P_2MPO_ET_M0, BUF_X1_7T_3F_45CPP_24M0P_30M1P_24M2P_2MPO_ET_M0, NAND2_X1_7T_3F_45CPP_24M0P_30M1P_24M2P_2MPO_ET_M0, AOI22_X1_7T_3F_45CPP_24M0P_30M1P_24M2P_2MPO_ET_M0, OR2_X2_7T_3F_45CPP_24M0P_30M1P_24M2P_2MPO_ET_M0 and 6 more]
MACRO XOR2_X1_7T_3F_45CPP_24M0P_30M1P_24M2P_2MPO_ET_M0
  CLASS CORE ;
  ORIGIN 0 0 ;
  FOREIGN XOR2_X1_7T_3F_45CPP_24M0P_30M1P_24M2P_2MPO_ET_M0 0 0 ;
  SIZE 0.2700 BY 0.1680 ;
  SYMMETRY X Y ;
  SITE coresite ;
  PIN Z
    DIRECTION OUTPUT ;
    USE SIGNAL ;
    PORT
      LAYER M1 ;
        RECT 0.1725 0.1200 0.1875 0.0240 ;
    END
  END Z
  PIN A1
    DIRECTION INPUT ;
    USE SIGNAL ;
    PORT
      LAYER M1 ;
        RECT 0.1425 0.1200 0.1575 0.0720 ;
    END
  END A1
  PIN A2
    DIRECTION INPUT ;
    USE SIGNAL ;
    PORT
      LAYER M1 ;
        RECT 0.2325 0.0720 0.2475 0.0240 ;
    END
  END A2
  PIN VDD
    DIRECTION INOUT ;
    USE POWER ;
    SHAPE ABUTMENT ;
    PORT
      LAYER M0 ;
        RECT 0.0000 0.1500 0.2700 0.1860 ;
    END
  END VDD
  PIN VSS
    DIRECTION INOUT ;
    USE GROUND ;
    SHAPE ABUTMENT ;
    PORT
      LAYER M0 ;
        RECT 0.0000 -0.0180 0.2700 0.0180 ;
    END
  END VSS
  OBS
      LAYER M1 ;
        RECT 0.0825 0.1200 0.0975 0.0240 ;
  END
END XOR2_X1_7T_3F_45CPP_24M0P_30M1P_24M2P_2MPO_ET_M0

MACRO LHQ_X1_7T_3F_45CPP_24M0P_30M1P_24M2P_2MPO_ET_M0
  CLASS CORE ;
  ORIGIN 0 0 ;
  FOREIGN LHQ_X1_7T_3F_45CPP_24M0P_30M1P_24M2P_2MPO_ET_M0 0 0 ;
  SIZE 0.4950 BY 0.1680 ;
  SYMMETRY X Y ;
  SITE coresite ;
  PIN Q
    DIRECTION OUTPUT ;
    USE SIGNAL ;
    PORT
      LAYER M1 ;
        RECT 0.1125 0.1200 0.1275 0.0480 ;
    END
  END Q
  PIN D
    DIRECTION INPUT ;
    USE SIGNAL ;
    PORT
      LAYER M1 ;
        RECT 0.2625 0.0720 0.2775 0.0240 ;
    END
  END D
  PIN E
    DIRECTION INPUT ;
    USE SIGNAL ;
    PORT
      LAYER M1 ;
        RECT 0.0525 0.0720 0.0675 0.0240 ;
    END
  END E
  PIN VDD
    DIRECTION INOUT ;
    USE POWER ;
    SHAPE ABUTMENT ;
    PORT
      LAYER M0 ;
        RECT 0.0000 0.1500 0.4950 0.1860 ;
    END
  END VDD
  PIN VSS
    DIRECTION INOUT ;
    USE GROUND ;
    SHAPE ABUTMENT ;
    PORT
      LAYER M0 ;
        RECT 0.0000 -0.0180 0.4950 0.0180 ;
    END
  END VSS
  OBS
      LAYER M1 ;
        RECT 0.3525 0.1440 0.3675 0.0240 ;
        RECT 0.2025 0.1200 0.2175 0.0240 ;
        RECT 0.4725 0.1200 0.4875 0.0240 ;
        RECT 0.0225 0.1200 0.0375 0.0240 ;
        RECT 0.4125 0.1200 0.4275 0.0480 ;
  END
END LHQ_X1_7T_3F_45CPP_24M0P_30M1P_24M2P_2MPO_ET_M0

MACRO BUF_X1_7T_3F_45CPP_24M0P_30M1P_24M2P_2MPO_ET_M0
  CLASS CORE ;
  ORIGIN 0 0 ;
  FOREIGN BUF_X1_7T_3F_45CPP_24M0P_30M1P_24M2P_2MPO_ET_M0 0 0 ;
  SIZE 0.1350 BY 0.1680 ;
  SYMMETRY X Y ;
  SITE coresite ;
  PIN Z
    DIRECTION OUTPUT ;
    USE SIGNAL ;
    PORT
      LAYER M1 ;
        RECT 0.1125 0.1200 0.1275 0.0480 ;
    END
  END Z
  PIN I
    DIRECTION INPUT ;
    USE SIGNAL ;
    PORT
      LAYER M1 ;
        RECT 0.0225 0.0720 0.0375 0.0240 ;
    END
  END I
  PIN VDD
    DIRECTION INOUT ;
    USE POWER ;
    SHAPE ABUTMENT ;
    PORT
      LAYER M0 ;
        RECT 0.0000 0.1500 0.1350 0.1860 ;
    END
  END VDD
  PIN VSS
    DIRECTION INOUT ;
    USE GROUND ;
    SHAPE ABUTMENT ;
    PORT
      LAYER M0 ;
        RECT 0.0000 -0.0180 0.1350 0.0180 ;
    END
  END VSS
  OBS
      LAYER M1 ;
        RECT 0.0525 0.1200 0.0675 0.0240 ;
  END
END BUF_X1_7T_3F_45CPP_24M0P_30M1P_24M2P_2MPO_ET_M0

MACRO NAND2_X1_7T_3F_45CPP_24M0P_30M1P_24M2P_2MPO_ET_M0
  CLASS CORE ;
  ORIGIN 0 0 ;
  FOREIGN NAND2_X1_7T_3F_45CPP_24M0P_30M1P_24M2P_2MPO_ET_M0 0 0 ;
  SIZE 0.1350 BY 0.1680 ;
  SYMMETRY X Y ;
  SITE coresite ;
  PIN ZN
    DIRECTION OUTPUT ;
    USE SIGNAL ;
    PORT
      LAYER M1 ;
        RECT 0.0825 0.1200 0.0975 0.0480 ;
    END
  END ZN
  PIN A1
    DIRECTION INPUT ;
    USE SIGNAL ;
    PORT
      LAYER M1 ;
        RECT 0.1125 0.0720 0.1275 0.0240 ;
    END
  END A1
  PIN A2
    DIRECTION INPUT ;
    USE SIGNAL ;
    PORT
      LAYER M1 ;
        RECT 0.0225 0.0720 0.0375 0.0240 ;
    END
  END A2
  PIN VDD
    DIRECTION INOUT ;
    USE POWER ;
    SHAPE ABUTMENT ;
    PORT
      LAYER M0 ;
        RECT 0.0000 0.1500 0.1350 0.1860 ;
    END
  END VDD
  PIN VSS
    DIRECTION INOUT ;
    USE GROUND ;
    SHAPE ABUTMENT ;
    PORT
      LAYER M0 ;
        RECT 0.0000 -0.0180 0.1350 0.0180 ;
    END
  END VSS
END NAND2_X1_7T_3F_45CPP_24M0P_30M1P_24M2P_2MPO_ET_M0

MACRO AOI22_X1_7T_3F_45CPP_24M0P_30M1P_24M2P_2MPO_ET_M0
  CLASS CORE ;
  ORIGIN 0 0 ;
  FOREIGN AOI22_X1_7T_3F_45CPP_24M0P_30M1P_24M2P_2MPO_ET_M0 0 0 ;
  SIZE 0.2250 BY 0.1680 ;
  SYMMETRY X Y ;
  SITE coresite ;
  PIN A2
    DIRECTION INPUT ;
    USE SIGNAL ;
    PORT
      LAYER M1 ;
        RECT 0.0825 0.0960 0.0975 0.0480 ;
    END
  END A2
  PIN A1
    DIRECTION INPUT ;
    USE SIGNAL ;
    PORT
      LAYER M1 ;
        RECT 0.1125 0.0960 0.1275 0.0480 ;
    END
  END A1
  PIN ZN
    DIRECTION OUTPUT ;
    USE SIGNAL ;
    PORT
      LAYER M1 ;
        RECT 0.1725 0.1200 0.1875 0.0480 ;
    END
  END ZN
  PIN B1
    DIRECTION INPUT ;
    USE SIGNAL ;
    PORT
      LAYER M1 ;
        RECT 0.2025 0.0960 0.2175 0.0480 ;
    END
  END B1
  PIN B2
    DIRECTION INPUT ;
    USE SIGNAL ;
    PORT
      LAYER M1 ;
        RECT 0.0225 0.0720 0.0375 0.0240 ;
    END
  END B2
  PIN VDD
    DIRECTION INOUT ;
    USE POWER ;
    SHAPE ABUTMENT ;
    PORT
      LAYER M0 ;
        RECT 0.0000 0.1500 0.2250 0.1860 ;
    END
  END VDD
  PIN VSS
    DIRECTION INOUT ;
    USE GROUND ;
    SHAPE ABUTMENT ;
    PORT
      LAYER M0 ;
        RECT 0.0000 -0.0180 0.2250 0.0180 ;
    END
  END VSS
END AOI22_X1_7T_3F_45CPP_24M0P_30M1P_24M2P_2MPO_ET_M0

MACRO OR2_X2_7T_3F_45CPP_24M0P_30M1P_24M2P_2MPO_ET_M0
  CLASS CORE ;
  ORIGIN 0 0 ;
  FOREIGN OR2_X2_7T_3F_45CPP_24M0P_30M1P_24M2P_2MPO_ET_M0 0 0 ;
  SIZE 0.2250 BY 0.1680 ;
  SYMMETRY X Y ;
  SITE coresite ;
  PIN Z
    DIRECTION OUTPUT ;
    USE SIGNAL ;
    PORT
      LAYER M1 ;
        RECT 0.1725 0.1200 0.1875 0.0480 ;
    END
  END Z
  PIN A1
    DIRECTION INPUT ;
    USE SIGNAL ;
    PORT
      LAYER M1 ;
        RECT 0.0225 0.0960 0.0375 0.0480 ;
    END
  END A1
  PIN A2
    DIRECTION INPUT ;
    USE SIGNAL ;
    PORT
      LAYER M1 ;
        RECT 0.0825 0.0720 0.0975 0.0240 ;
    END
  END A2
  PIN VDD
    DIRECTION INOUT ;
    USE POWER ;
    SHAPE ABUTMENT ;
    PORT
      LAYER M0 ;
        RECT 0.0000 0.1500 0.2250 0.1860 ;
    END
  END VDD
  PIN VSS
    DIRECTION INOUT ;
    USE GROUND ;
    SHAPE ABUTMENT ;
    PORT
      LAYER M0 ;
        RECT 0.0000 -0.0180 0.2250 0.0180 ;
    END
  END VSS
  OBS
      LAYER M1 ;
        RECT 0.0525 0.1200 0.0675 0.0240 ;
  END
END OR2_X2_7T_3F_45CPP_24M0P_30M1P_24M2P_2MPO_ET_M0

MACRO BUF_X8_7T_3F_45CPP_24M0P_30M1P_24M2P_2MPO_ET_M0
  CLASS CORE ;
  ORIGIN 0 0 ;
  FOREIGN BUF_X8_7T_3F_45CPP_24M0P_30M1P_24M2P_2MPO_ET_M0 0 0 ;
  SIZE 0.5850 BY 0.1680 ;
  SYMMETRY X Y ;
  SITE coresite ;
  PIN Z
    DIRECTION OUTPUT ;
    USE SIGNAL ;
    PORT
      LAYER M1 ;
        RECT 0.3225 0.1200 0.3375 0.0480 ;
    END
  END Z
  PIN I
    DIRECTION INPUT ;
    USE SIGNAL ;
    PORT
      LAYER M1 ;
        RECT 0.1725 0.0720 0.1875 0.0240 ;
    END
  END I
  PIN VDD
    DIRECTION INOUT ;
    USE POWER ;
    SHAPE ABUTMENT ;
    PORT
      LAYER M0 ;
        RECT 0.0000 0.1500 0.5850 0.1860 ;
    END
  END VDD
  PIN VSS
    DIRECTION INOUT ;
    USE GROUND ;
    SHAPE ABUTMENT ;
    PORT
      LAYER M0 ;
        RECT 0.0000 -0.0180 0.5850 0.0180 ;
    END
  END VSS
  OBS
      LAYER M1 ;
        RECT 0.2625 0.0960 0.2775 0.0240 ;
        RECT 0.1425 0.1200 0.1575 0.0480 ;
  END
END BUF_X8_7T_3F_45CPP_24M0P_30M1P_24M2P_2MPO_ET_M0

MACRO BUF_X4_7T_3F_45CPP_24M0P_30M1P_24M2P_2MPO_ET_M0
  CLASS CORE ;
  ORIGIN 0 0 ;
  FOREIGN BUF_X4_7T_3F_45CPP_24M0P_30M1P_24M2P_2MPO_ET_M0 0 0 ;
  SIZE 0.3150 BY 0.1680 ;
  SYMMETRY X Y ;
  SITE coresite ;
  PIN Z
    DIRECTION OUTPUT ;
    USE SIGNAL ;
    PORT
      LAYER M1 ;
        RECT 0.1725 0.1200 0.1875 0.0480 ;
    END
  END Z
  PIN I
    DIRECTION INPUT ;
    USE SIGNAL ;
    PORT
      LAYER M1 ;
        RECT 0.0525 0.0720 0.0675 0.0240 ;
    END
  END I
  PIN VDD
    DIRECTION INOUT ;
    USE POWER ;
    SHAPE ABUTMENT ;
    PORT
      LAYER M0 ;
        RECT 0.0000 0.1500 0.3150 0.1860 ;
    END
  END VDD
  PIN VSS
    DIRECTION INOUT ;
    USE GROUND ;
    SHAPE ABUTMENT ;
    PORT
      LAYER M0 ;
        RECT 0.0000 -0.0180 0.3150 0.0180 ;
    END
  END VSS
  OBS
      LAYER M1 ;
        RECT 0.0825 0.1200 0.0975 0.0480 ;
        RECT 0.1425 0.0960 0.1575 0.0240 ;
  END
END BUF_X4_7T_3F_45CPP_24M0P_30M1P_24M2P_2MPO_ET_M0

MACRO AOI21_X2_7T_3F_45CPP_24M0P_30M1P_24M2P_2MPO_ET_M0
  CLASS CORE ;
  ORIGIN 0 0 ;
  FOREIGN AOI21_X2_7T_3F_45CPP_24M0P_30M1P_24M2P_2MPO_ET_M0 0 0 ;
  SIZE 0.3600 BY 0.1680 ;
  SYMMETRY X Y ;
  SITE coresite ;
  PIN A1
    DIRECTION INPUT ;
    USE SIGNAL ;
    PORT
      LAYER M1 ;
        RECT 0.2625 0.0960 0.2775 0.0480 ;
    END
  END A1
  PIN A2
    DIRECTION INPUT ;
    USE SIGNAL ;
    PORT
      LAYER M1 ;
        RECT 0.1125 0.0960 0.1275 0.0240 ;
    END
  END A2
  PIN ZN
    DIRECTION OUTPUT ;
    USE SIGNAL ;
    PORT
      LAYER M1 ;
        RECT 0.2025 0.1440 0.2175 0.0240 ;
    END
  END ZN
  PIN B
    DIRECTION INPUT ;
    USE SIGNAL ;
    PORT
      LAYER M1 ;
        RECT 0.1725 0.0960 0.1875 0.0480 ;
    END
  END B
  PIN VDD
    DIRECTION INOUT ;
    USE POWER ;
    SHAPE ABUTMENT ;
    PORT
      LAYER M0 ;
        RECT 0.0000 0.1500 0.3600 0.1860 ;
    END
  END VDD
  PIN VSS
    DIRECTION INOUT ;
    USE GROUND ;
    SHAPE ABUTMENT ;
    PORT
      LAYER M0 ;
        RECT 0.0000 -0.0180 0.3600 0.0180 ;
    END
  END VSS
END AOI21_X2_7T_3F_45CPP_24M0P_30M1P_24M2P_2MPO_ET_M0

MACRO INV_X1_7T_3F_45CPP_24M0P_30M1P_24M2P_2MPO_ET_M0
  CLASS CORE ;
  ORIGIN 0 0 ;
  FOREIGN INV_X1_7T_3F_45CPP_24M0P_30M1P_24M2P_2MPO_ET_M0 0 0 ;
  SIZE 0.0900 BY 0.1680 ;
  SYMMETRY X Y ;
  SITE coresite ;
  PIN ZN
    DIRECTION OUTPUT ;
    USE SIGNAL ;
    PORT
      LAYER M1 ;
        RECT 0.0525 0.1200 0.0675 0.0480 ;
    END
  END ZN
  PIN I
    DIRECTION INPUT ;
    USE SIGNAL ;
    PORT
      LAYER M1 ;
        RECT 0.0225 0.0720 0.0375 0.0240 ;
    END
  END I
  PIN VDD
    DIRECTION INOUT ;
    USE POWER ;
    SHAPE ABUTMENT ;
    PORT
      LAYER M0 ;
        RECT 0.0000 0.1500 0.0900 0.1860 ;
    END
  END VDD
  PIN VSS
    DIRECTION INOUT ;
    USE GROUND ;
    SHAPE ABUTMENT ;
    PORT
      LAYER M0 ;
        RECT 0.0000 -0.0180 0.0900 0.0180 ;
    END
  END VSS
END INV_X1_7T_3F_45CPP_24M0P_30M1P_24M2P_2MPO_ET_M0

MACRO MUX2_X1_7T_3F_45CPP_24M0P_30M1P_24M2P_2MPO_ET_M0
  CLASS CORE ;
  ORIGIN 0 0 ;
  FOREIGN MUX2_X1_7T_3F_45CPP_24M0P_30M1P_24M2P_2MPO_ET_M0 0 0 ;
  SIZE 0.3600 BY 0.1680 ;
  SYMMETRY X Y ;
  SITE coresite ;
  PIN Z
    DIRECTION OUTPUT ;
    USE SIGNAL ;
    PORT
      LAYER M1 ;
        RECT 0.3225 0.1440 0.3375 0.0240 ;
    END
  END Z
  PIN I0
    DIRECTION INPUT ;
    USE SIGNAL ;
    PORT
      LAYER M1 ;
        RECT 0.1425 0.0720 0.1575 0.0240 ;
    END
  END I0
  PIN I1
    DIRECTION INPUT ;
    USE SIGNAL ;
    PORT
      LAYER M1 ;
        RECT 0.2625 0.0720 0.2775 0.0240 ;
    END
  END I1
  PIN S
    DIRECTION INPUT ;
    USE SIGNAL ;
    PORT
      LAYER M1 ;
        RECT 0.1125 0.0960 0.1275 0.0480 ;
    END
  END S
  PIN VDD
    DIRECTION INOUT ;
    USE POWER ;
    SHAPE ABUTMENT ;
    PORT
      LAYER M0 ;
        RECT 0.0000 0.1500 0.3600 0.1860 ;
    END
  END VDD
  PIN VSS
    DIRECTION INOUT ;
    USE GROUND ;
    SHAPE ABUTMENT ;
    PORT
      LAYER M0 ;
        RECT 0.0000 -0.0180 0.3600 0.0180 ;
    END
  END VSS
  OBS
      LAYER M1 ;
        RECT 0.0825 0.1200 0.0975 0.0240 ;
        RECT 0.2925 0.1200 0.3075 0.0480 ;
        RECT 0.2025 0.1440 0.2175 0.0240 ;
        RECT 0.2325 0.0960 0.2475 0.0480 ;
        RECT 0.0225 0.0960 0.0375 0.0240 ;
  END
END MUX2_X1_7T_3F_45CPP_24M0P_30M1P_24M2P_2MPO_ET_M0

MACRO AND3_X1_7T_3F_45CPP_24M0P_30M1P_24M2P_2MPO_ET_M0
  CLASS CORE ;
  ORIGIN 0 0 ;
  FOREIGN AND3_X1_7T_3F_45CPP_24M0P_30M1P_24M2P_2MPO_ET_M0 0 0 ;
  SIZE 0.2250 BY 0.1680 ;
  SYMMETRY X Y ;
  SITE coresite ;
  PIN Z
    DIRECTION OUTPUT ;
    USE SIGNAL ;
    PORT
      LAYER M1 ;
        RECT 0.1725 0.1200 0.1875 0.0480 ;
    END
  END Z
  PIN A1
    DIRECTION INPUT ;
    USE SIGNAL ;
    PORT
      LAYER M1 ;
        RECT 0.0225 0.0720 0.0375 0.0240 ;
    END
  END A1
  PIN A2
    DIRECTION INPUT ;
    USE SIGNAL ;
    PORT
      LAYER M1 ;
        RECT 0.0825 0.0960 0.0975 0.0480 ;
    END
  END A2
  PIN A3
    DIRECTION INPUT ;
    USE SIGNAL ;
    PORT
      LAYER M1 ;
        RECT 0.1125 0.0960 0.1275 0.0480 ;
    END
  END A3
  PIN VDD
    DIRECTION INOUT ;
    USE POWER ;
    SHAPE ABUTMENT ;
    PORT
      LAYER M0 ;
        RECT 0.0000 0.1500 0.2250 0.1860 ;
    END
  END VDD
  PIN VSS
    DIRECTION INOUT ;
    USE GROUND ;
    SHAPE ABUTMENT ;
    PORT
      LAYER M0 ;
        RECT 0.0000 -0.0180 0.2250 0.0180 ;
    END
  END VSS
  OBS
      LAYER M1 ;
        RECT 0.0525 0.1200 0.0675 0.0240 ;
  END
END AND3_X1_7T_3F_45CPP_24M0P_30M1P_24M2P_2MPO_ET_M0

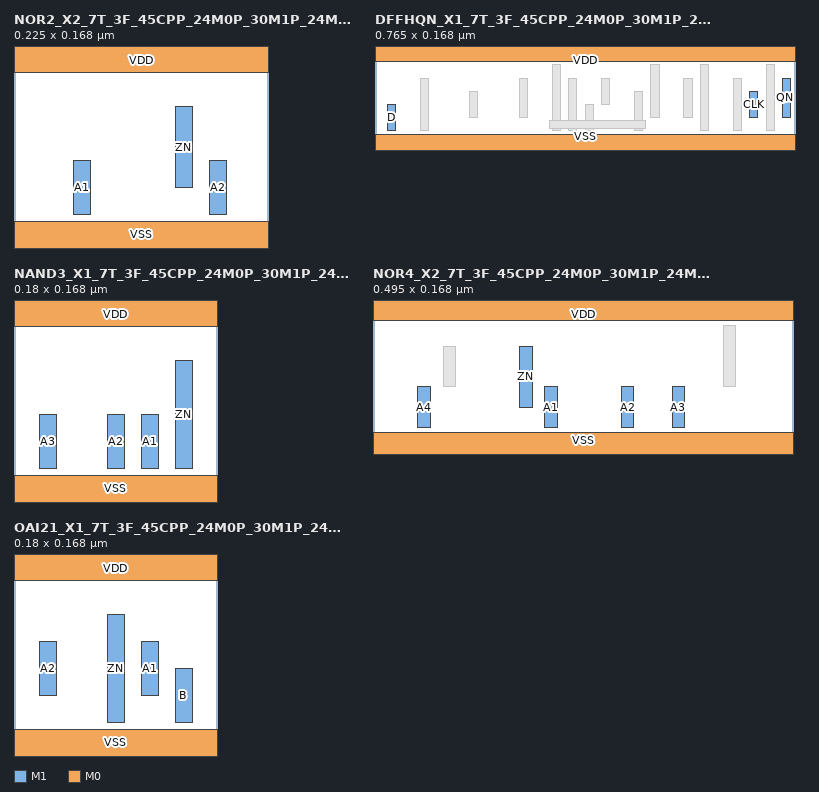
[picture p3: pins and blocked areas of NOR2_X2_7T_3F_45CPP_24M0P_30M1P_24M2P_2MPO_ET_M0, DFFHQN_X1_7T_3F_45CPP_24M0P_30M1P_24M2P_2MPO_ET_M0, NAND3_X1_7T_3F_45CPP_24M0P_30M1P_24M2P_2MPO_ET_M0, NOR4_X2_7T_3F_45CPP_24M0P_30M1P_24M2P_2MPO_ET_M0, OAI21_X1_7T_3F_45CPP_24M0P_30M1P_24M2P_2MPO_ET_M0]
MACRO NOR2_X2_7T_3F_45CPP_24M0P_30M1P_24M2P_2MPO_ET_M0
  CLASS CORE ;
  ORIGIN 0 0 ;
  FOREIGN NOR2_X2_7T_3F_45CPP_24M0P_30M1P_24M2P_2MPO_ET_M0 0 0 ;
  SIZE 0.2250 BY 0.1680 ;
  SYMMETRY X Y ;
  SITE coresite ;
  PIN A2
    DIRECTION INPUT ;
    USE SIGNAL ;
    PORT
      LAYER M1 ;
        RECT 0.1725 0.0720 0.1875 0.0240 ;
    END
  END A2
  PIN A1
    DIRECTION INPUT ;
    USE SIGNAL ;
    PORT
      LAYER M1 ;
        RECT 0.0525 0.0720 0.0675 0.0240 ;
    END
  END A1
  PIN ZN
    DIRECTION OUTPUT ;
    USE SIGNAL ;
    PORT
      LAYER M1 ;
        RECT 0.1425 0.1200 0.1575 0.0480 ;
    END
  END ZN
  PIN VDD
    DIRECTION INOUT ;
    USE POWER ;
    SHAPE ABUTMENT ;
    PORT
      LAYER M0 ;
        RECT 0.0000 0.1500 0.2250 0.1860 ;
    END
  END VDD
  PIN VSS
    DIRECTION INOUT ;
    USE GROUND ;
    SHAPE ABUTMENT ;
    PORT
      LAYER M0 ;
        RECT 0.0000 -0.0180 0.2250 0.0180 ;
    END
  END VSS
END NOR2_X2_7T_3F_45CPP_24M0P_30M1P_24M2P_2MPO_ET_M0

MACRO DFFHQN_X1_7T_3F_45CPP_24M0P_30M1P_24M2P_2MPO_ET_M0
  CLASS CORE ;
  ORIGIN 0 0 ;
  FOREIGN DFFHQN_X1_7T_3F_45CPP_24M0P_30M1P_24M2P_2MPO_ET_M0 0 0 ;
  SIZE 0.7650 BY 0.1680 ;
  SYMMETRY X Y ;
  SITE coresite ;
  PIN D
    DIRECTION INPUT ;
    USE SIGNAL ;
    PORT
      LAYER M1 ;
        RECT 0.0225 0.0720 0.0375 0.0240 ;
    END
  END D
  PIN CLK
    DIRECTION INPUT ;
    USE SIGNAL ;
    PORT
      LAYER M1 ;
        RECT 0.6825 0.0960 0.6975 0.0480 ;
    END
  END CLK
  PIN QN
    DIRECTION OUTPUT ;
    USE SIGNAL ;
    PORT
      LAYER M1 ;
        RECT 0.7425 0.1200 0.7575 0.0480 ;
    END
  END QN
  PIN VDD
    DIRECTION INOUT ;
    USE POWER ;
    SHAPE ABUTMENT ;
    PORT
      LAYER M0 ;
        RECT 0.0000 0.1500 0.7650 0.1860 ;
    END
  END VDD
  PIN VSS
    DIRECTION INOUT ;
    USE GROUND ;
    SHAPE ABUTMENT ;
    PORT
      LAYER M0 ;
        RECT 0.0000 -0.0180 0.7650 0.0180 ;
    END
  END VSS
  OBS
      LAYER V1 ;
        RECT 0.4730 0.0290 0.4870 0.0430 ;
        RECT 0.3830 0.0290 0.3970 0.0430 ;
        RECT 0.3230 0.0290 0.3370 0.0430 ;
      LAYER M1 ;
        RECT 0.0825 0.1200 0.0975 0.0240 ;
        RECT 0.3525 0.1200 0.3675 0.0240 ;
        RECT 0.7125 0.1440 0.7275 0.0240 ;
        RECT 0.2625 0.1200 0.2775 0.0480 ;
        RECT 0.4725 0.0960 0.4875 0.0240 ;
        RECT 0.5925 0.1440 0.6075 0.0240 ;
        RECT 0.3825 0.0720 0.3975 0.0240 ;
        RECT 0.5025 0.1440 0.5175 0.0480 ;
        RECT 0.3225 0.1440 0.3375 0.0240 ;
        RECT 0.6525 0.1200 0.6675 0.0240 ;
        RECT 0.5625 0.1200 0.5775 0.0480 ;
        RECT 0.4125 0.1200 0.4275 0.0720 ;
        RECT 0.1725 0.0960 0.1875 0.0480 ;
      LAYER M2 ;
        RECT 0.3180 0.0290 0.4920 0.0430 ;
  END
END DFFHQN_X1_7T_3F_45CPP_24M0P_30M1P_24M2P_2MPO_ET_M0

MACRO NAND3_X1_7T_3F_45CPP_24M0P_30M1P_24M2P_2MPO_ET_M0
  CLASS CORE ;
  ORIGIN 0 0 ;
  FOREIGN NAND3_X1_7T_3F_45CPP_24M0P_30M1P_24M2P_2MPO_ET_M0 0 0 ;
  SIZE 0.1800 BY 0.1680 ;
  SYMMETRY X Y ;
  SITE coresite ;
  PIN ZN
    DIRECTION OUTPUT ;
    USE SIGNAL ;
    PORT
      LAYER M1 ;
        RECT 0.1425 0.1200 0.1575 0.0240 ;
    END
  END ZN
  PIN A1
    DIRECTION INPUT ;
    USE SIGNAL ;
    PORT
      LAYER M1 ;
        RECT 0.1125 0.0720 0.1275 0.0240 ;
    END
  END A1
  PIN A2
    DIRECTION INPUT ;
    USE SIGNAL ;
    PORT
      LAYER M1 ;
        RECT 0.0825 0.0720 0.0975 0.0240 ;
    END
  END A2
  PIN A3
    DIRECTION INPUT ;
    USE SIGNAL ;
    PORT
      LAYER M1 ;
        RECT 0.0225 0.0720 0.0375 0.0240 ;
    END
  END A3
  PIN VDD
    DIRECTION INOUT ;
    USE POWER ;
    SHAPE ABUTMENT ;
    PORT
      LAYER M0 ;
        RECT 0.0000 0.1500 0.1800 0.1860 ;
    END
  END VDD
  PIN VSS
    DIRECTION INOUT ;
    USE GROUND ;
    SHAPE ABUTMENT ;
    PORT
      LAYER M0 ;
        RECT 0.0000 -0.0180 0.1800 0.0180 ;
    END
  END VSS
END NAND3_X1_7T_3F_45CPP_24M0P_30M1P_24M2P_2MPO_ET_M0

MACRO NOR4_X2_7T_3F_45CPP_24M0P_30M1P_24M2P_2MPO_ET_M0
  CLASS CORE ;
  ORIGIN 0 0 ;
  FOREIGN NOR4_X2_7T_3F_45CPP_24M0P_30M1P_24M2P_2MPO_ET_M0 0 0 ;
  SIZE 0.4950 BY 0.1680 ;
  SYMMETRY X Y ;
  SITE coresite ;
  PIN A4
    DIRECTION INPUT ;
    USE SIGNAL ;
    PORT
      LAYER M1 ;
        RECT 0.0525 0.0720 0.0675 0.0240 ;
    END
  END A4
  PIN A3
    DIRECTION INPUT ;
    USE SIGNAL ;
    PORT
      LAYER M1 ;
        RECT 0.3525 0.0720 0.3675 0.0240 ;
    END
  END A3
  PIN A2
    DIRECTION INPUT ;
    USE SIGNAL ;
    PORT
      LAYER M1 ;
        RECT 0.2925 0.0720 0.3075 0.0240 ;
    END
  END A2
  PIN A1
    DIRECTION INPUT ;
    USE SIGNAL ;
    PORT
      LAYER M1 ;
        RECT 0.2025 0.0720 0.2175 0.0240 ;
    END
  END A1
  PIN ZN
    DIRECTION OUTPUT ;
    USE SIGNAL ;
    PORT
      LAYER M1 ;
        RECT 0.1725 0.1200 0.1875 0.0480 ;
    END
  END ZN
  PIN VDD
    DIRECTION INOUT ;
    USE POWER ;
    SHAPE ABUTMENT ;
    PORT
      LAYER M0 ;
        RECT 0.0000 0.1500 0.4950 0.1860 ;
    END
  END VDD
  PIN VSS
    DIRECTION INOUT ;
    USE GROUND ;
    SHAPE ABUTMENT ;
    PORT
      LAYER M0 ;
        RECT 0.0000 -0.0180 0.4950 0.0180 ;
    END
  END VSS
  OBS
      LAYER M1 ;
        RECT 0.0825 0.1200 0.0975 0.0720 ;
        RECT 0.4125 0.1440 0.4275 0.0720 ;
  END
END NOR4_X2_7T_3F_45CPP_24M0P_30M1P_24M2P_2MPO_ET_M0

MACRO OAI21_X1_7T_3F_45CPP_24M0P_30M1P_24M2P_2MPO_ET_M0
  CLASS CORE ;
  ORIGIN 0 0 ;
  FOREIGN OAI21_X1_7T_3F_45CPP_24M0P_30M1P_24M2P_2MPO_ET_M0 0 0 ;
  SIZE 0.1800 BY 0.1680 ;
  SYMMETRY X Y ;
  SITE coresite ;
  PIN B
    DIRECTION INPUT ;
    USE SIGNAL ;
    PORT
      LAYER M1 ;
        RECT 0.1425 0.0720 0.1575 0.0240 ;
    END
  END B
  PIN A1
    DIRECTION INPUT ;
    USE SIGNAL ;
    PORT
      LAYER M1 ;
        RECT 0.1125 0.0960 0.1275 0.0480 ;
    END
  END A1
  PIN ZN
    DIRECTION OUTPUT ;
    USE SIGNAL ;
    PORT
      LAYER M1 ;
        RECT 0.0825 0.1200 0.0975 0.0240 ;
    END
  END ZN
  PIN A2
    DIRECTION INPUT ;
    USE SIGNAL ;
    PORT
      LAYER M1 ;
        RECT 0.0225 0.0960 0.0375 0.0480 ;
    END
  END A2
  PIN VDD
    DIRECTION INOUT ;
    USE POWER ;
    SHAPE ABUTMENT ;
    PORT
      LAYER M0 ;
        RECT 0.0000 0.1500 0.1800 0.1860 ;
    END
  END VDD
  PIN VSS
    DIRECTION INOUT ;
    USE GROUND ;
    SHAPE ABUTMENT ;
    PORT
      LAYER M0 ;
        RECT 0.0000 -0.0180 0.1800 0.0180 ;
    END
  END VSS
END OAI21_X1_7T_3F_45CPP_24M0P_30M1P_24M2P_2MPO_ET_M0

END LIBRARY
